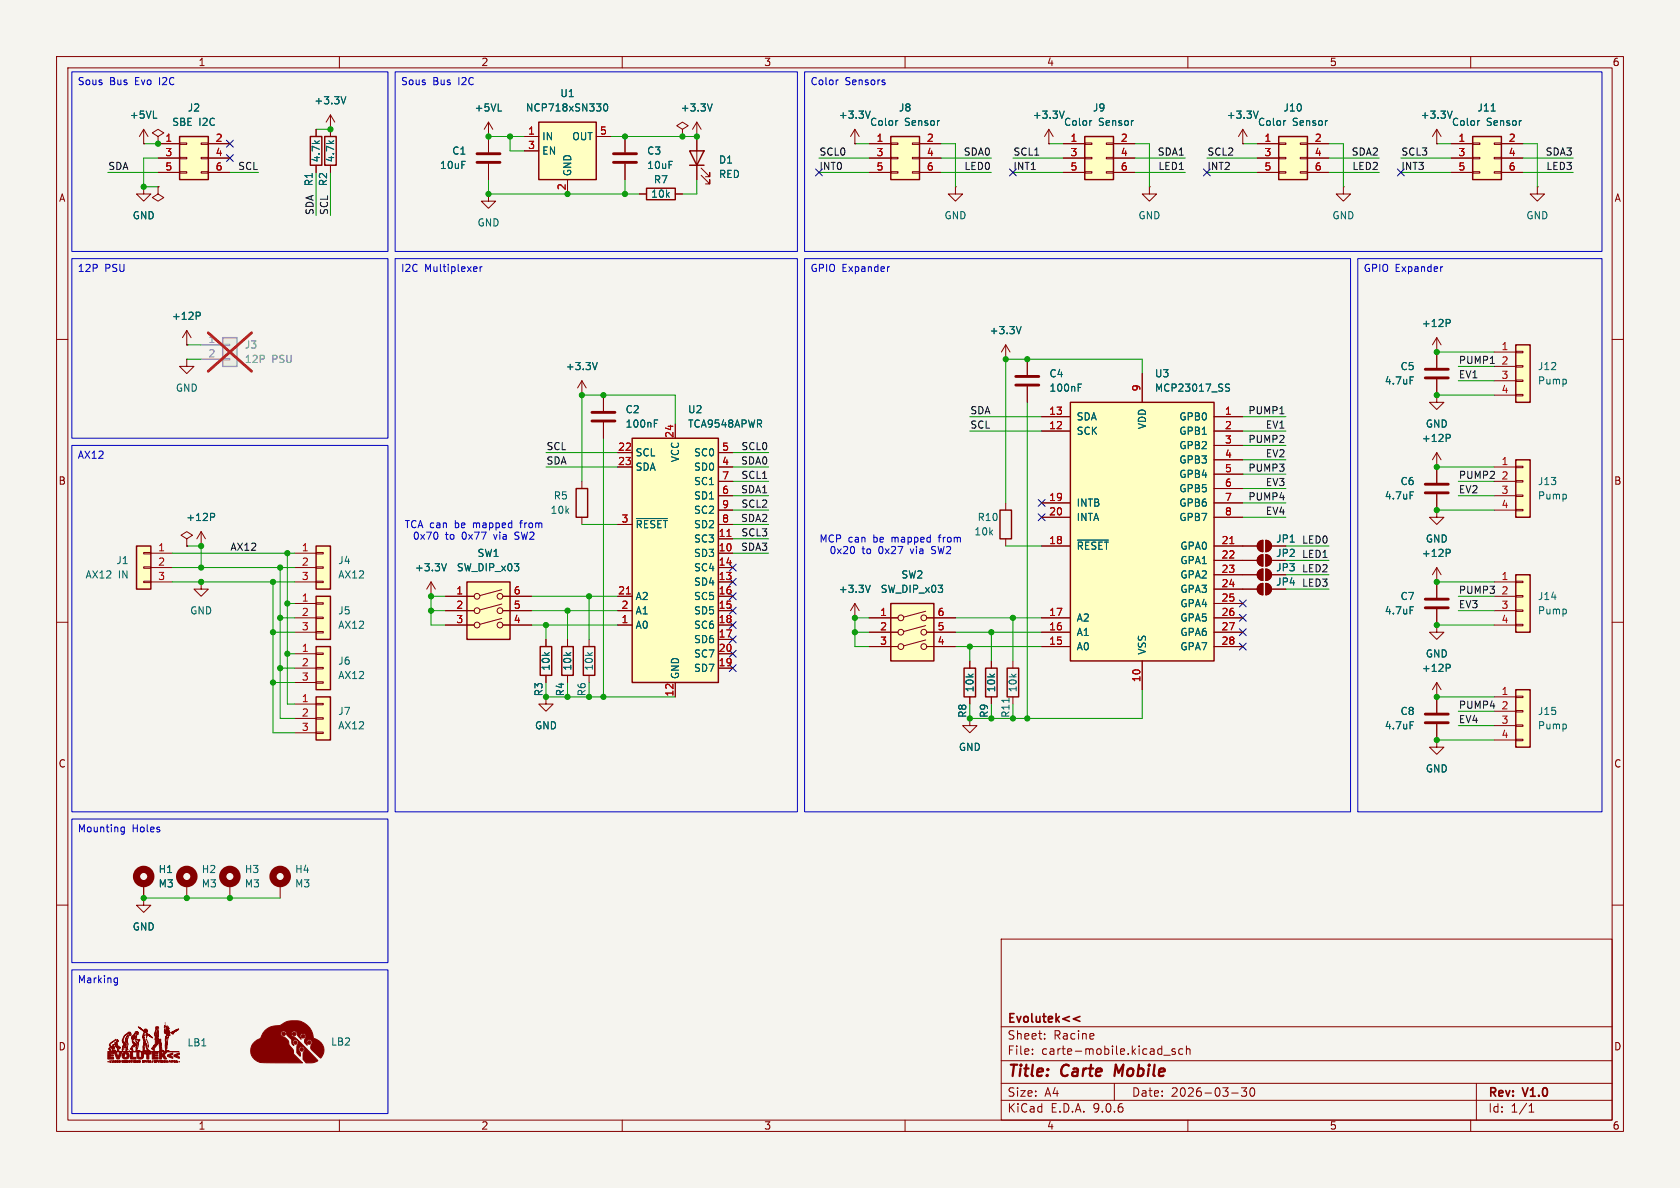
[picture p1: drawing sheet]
<svg xmlns="http://www.w3.org/2000/svg" width="297mm" height="210mm" viewBox="0 0 297 210" stroke-linecap="round" stroke-linejoin="round" font-family="sans-serif">
<defs><g id="words">
<g font-size="2.8" fill="#840000">
<text x="178" y="190.9">Title:</text>
<text x="187.7" y="190.9">Carte</text>
<text x="197.9" y="190.9">Mobile</text>
</g>
<g font-size="2.1" fill="#840000">
<text x="178" y="184">Sheet:</text>
<text x="178" y="181.2">Evolutek&lt;&lt;</text>
<text x="186.2" y="184">Racine</text>
<text x="178" y="186.7">File:</text>
<text x="184.1" y="186.7">carte-mobile.kicad_sch</text>
<text x="178" y="196.9">KiCad</text>
<text x="178" y="194.1">Size:</text>
<text x="184.7" y="194.1">A4</text>
<text x="185.7" y="196.9">E.D.A.</text>
<text x="193.3" y="196.9">9.0.6</text>
<text x="200" y="194.1">Date:</text>
<text x="207" y="194.1">2026-03-30</text>
<text x="263" y="194.3">Rev:</text>
<text x="263" y="196.9">Id:</text>
<text x="267.1" y="196.9">1/1</text>
<text x="269.4" y="194.3">V1.0</text>
</g>
<g font-size="1.8" fill="#840000">
<text x="35" y="11.9">1</text>
<text x="85" y="11.9">2</text>
<text x="135" y="11.9">3</text>
<text x="185" y="11.9">4</text>
<text x="235" y="11.9">5</text>
<text x="285" y="11.9">6</text>
<text x="10.3" y="35.9">A</text>
<text x="285.3" y="35.9">A</text>
<text x="10.3" y="85.9">B</text>
<text x="285.3" y="85.9">B</text>
<text x="96.1" y="123.2" transform="rotate(-90 96.1 123.2)">R3</text>
<text x="171" y="127" transform="rotate(-90 171 127)">R8</text>
<text x="10.3" y="135.9">C</text>
<text x="285.3" y="135.9">C</text>
<text x="10.3" y="185.9">D</text>
<text x="285.3" y="185.9">D</text>
<text x="35" y="199.9">1</text>
<text x="85" y="199.9">2</text>
<text x="135" y="199.9">3</text>
<text x="185" y="199.9">4</text>
<text x="235" y="199.9">5</text>
<text x="285" y="199.9">6</text>
</g>
<g font-size="1.8" fill="#0000c2">
<text x="13.7" y="15.4">Sous</text>
<text x="19.4" y="15.4">Bus</text>
<text x="24" y="15.4">Evo</text>
<text x="28.4" y="15.4">I2C</text>
<text x="70.8" y="15.4">Sous</text>
<text x="76.5" y="15.4">Bus</text>
<text x="81.1" y="15.4">I2C</text>
<text x="143.2" y="15.4">Color</text>
<text x="149.4" y="15.4">Sensors</text>
<text x="13.7" y="48.4">12P</text>
<text x="18.5" y="48.4">PSU</text>
<text x="70.8" y="48.4">I2C</text>
<text x="75.1" y="48.4">Multiplexer</text>
<text x="143.2" y="48.4">GPIO Expander</text>
<text x="241" y="48.4">GPIO Expander</text>
<text x="13.7" y="81.4">AX12</text>
<text x="71.4" y="93.6">TCA can</text>
<text x="72.9" y="95.6">0x70</text>
<text x="78.7" y="95.6">to</text>
<text x="80.5" y="93.6">be</text>
<text x="81.8" y="95.6">0x77</text>
<text x="83.9" y="93.6">mapped</text>
<text x="87.6" y="95.6">via</text>
<text x="91.5" y="95.6">SW2</text>
<text x="92.5" y="93.6">from</text>
<text x="144.8" y="96.1">MCP can</text>
<text x="146.6" y="98.2">0x20</text>
<text x="152.4" y="98.2">to</text>
<text x="154.5" y="96.1">be</text>
<text x="155.4" y="98.2">0x27</text>
<text x="157.9" y="96.1">mapped</text>
<text x="161.3" y="98.2">via</text>
<text x="165.1" y="98.2">SW2</text>
<text x="166.4" y="96.1">from</text>
<text x="13.7" y="147.5">Mounting</text>
<text x="23.4" y="147.5">Holes</text>
<text x="13.7" y="174.1">Marking</text>
</g>
<g font-size="1.8" fill="#006464">
<text x="99" y="17.4">U1</text>
<text x="22.8" y="21.2">+5VL</text>
<text x="30.3" y="22.5">SBE</text>
<text x="33.1" y="19.9">J2</text>
<text x="35.1" y="22.5">I2C</text>
<text x="55.5" y="18.6">+3.3V</text>
<text x="83.8" y="19.9">+5VL</text>
<text x="92.9" y="19.9">NCP718xSN330</text>
<text x="120.2" y="19.9">+3.3V</text>
<text x="148.2" y="21.2">+3.3V</text>
<text x="153.7" y="22.5">Color</text>
<text x="158.8" y="19.9">J8</text>
<text x="159.9" y="22.5">Sensor</text>
<text x="182.5" y="21.2">+3.3V</text>
<text x="188" y="22.5">Color</text>
<text x="193.1" y="19.9">J9</text>
<text x="194.2" y="22.5">Sensor</text>
<text x="216.8" y="21.2">+3.3V</text>
<text x="222.3" y="22.5">Color</text>
<text x="226.8" y="19.9">J10</text>
<text x="228.5" y="22.5">Sensor</text>
<text x="251.1" y="21.2">+3.3V</text>
<text x="256.6" y="22.5">Color</text>
<text x="261.1" y="19.9">J11</text>
<text x="262.8" y="22.5">Sensor</text>
<text x="56.7" y="28.8" transform="rotate(-90 56.7 28.8)">4.7k</text>
<text x="59.3" y="28.8" transform="rotate(-90 59.3 28.8)">4.7k</text>
<text x="79.9" y="27.5">C1</text>
<text x="95.8" y="25">IN</text>
<text x="95.8" y="27.5">EN</text>
<text x="101.1" y="25">OUT</text>
<text x="114.3" y="27.5">C3</text>
<text x="127" y="29.1">D1</text>
<text x="55.5" y="33" transform="rotate(-90 55.5 33)">R1</text>
<text x="58" y="33" transform="rotate(-90 58 33)">R2</text>
<text x="77.7" y="30.1">10uF</text>
<text x="101.2" y="31.2" transform="rotate(-90 101.2 31.2)">GND</text>
<text x="114.3" y="30.1">10uF</text>
<text x="115" y="35.2">10k</text>
<text x="115.5" y="32.6">R7</text>
<text x="127" y="31.7">RED</text>
<text x="23.4" y="39">GND</text>
<text x="84.3" y="40.2">GND</text>
<text x="166.9" y="39">GND</text>
<text x="201.2" y="39">GND</text>
<text x="235.5" y="39">GND</text>
<text x="269.7" y="39">GND</text>
<text x="30.3" y="56.7">+12P</text>
<text x="174.9" y="59.3">+3.3V</text>
<text x="251.3" y="58">+12P</text>
<text x="99.9" y="65.6">+3.3V</text>
<text x="247.5" y="65.6">C5</text>
<text x="271.8" y="65.6">J12</text>
<text x="31" y="69.4">GND</text>
<text x="185.4" y="66.9">C4</text>
<text x="185.4" y="69.4">100nF</text>
<text x="204.1" y="69.4">MCP23017_SS</text>
<text x="204.1" y="66.9">U3</text>
<text x="244.7" y="68.2">4.7uF</text>
<text x="271.8" y="68.2">Pump</text>
<text x="110.5" y="73.3">C2</text>
<text x="110.5" y="75.8">100nF</text>
<text x="121.5" y="73.3">U2</text>
<text x="121.5" y="75.8">TCA9548APWR</text>
<text x="190.2" y="74.5">SDA</text>
<text x="190.2" y="77.1">SCK</text>
<text x="202.8" y="76" transform="rotate(-90 202.8 76)">VDD</text>
<text x="208.4" y="74.5">GPB0</text>
<text x="208.4" y="77.1">GPB1</text>
<text x="252" y="75.8">GND</text>
<text x="112.3" y="80.9">SCL</text>
<text x="112.3" y="83.4">SDA</text>
<text x="120.2" y="81.8" transform="rotate(-90 120.2 81.8)">VCC</text>
<text x="122.6" y="80.9">SC0</text>
<text x="122.6" y="83.4">SD0</text>
<text x="208.4" y="79.6">GPB2</text>
<text x="208.4" y="82.1">GPB3</text>
<text x="251.3" y="78.3">+12P</text>
<text x="97.8" y="88.5">R5</text>
<text x="122.6" y="86">SC1</text>
<text x="122.6" y="88.5">SD1</text>
<text x="190.2" y="89.8">INTB</text>
<text x="208.4" y="84.7">GPB4</text>
<text x="208.4" y="87.2">GPB5</text>
<text x="208.4" y="89.8">GPB6</text>
<text x="244.7" y="88.5">4.7uF</text>
<text x="247.5" y="86">C6</text>
<text x="271.8" y="88.5">Pump</text>
<text x="271.8" y="86">J13</text>
<text x="32.8" y="92.3">+12P</text>
<text x="97.2" y="91">10k</text>
<text x="112.3" y="93.6">~{RESET}</text>
<text x="122.6" y="91">SC2</text>
<text x="122.6" y="93.6">SD2</text>
<text x="172.2" y="94.8">10k</text>
<text x="172.7" y="92.3">R10</text>
<text x="190.2" y="92.3">INTA</text>
<text x="208.4" y="92.3">GPB7</text>
<text x="20.5" y="99.9">J1</text>
<text x="59.7" y="99.9">J4</text>
<text x="73.3" y="101.2">+3.3V</text>
<text x="80.7" y="101.2">SW_DIP_x03</text>
<text x="84.3" y="98.7">SW1</text>
<text x="122.6" y="96.1">SC3</text>
<text x="122.6" y="98.7">SD3</text>
<text x="122.6" y="101.2">SC4</text>
<text x="190.2" y="97.4">~{RESET}</text>
<text x="208.6" y="97.4">GPA0</text>
<text x="208.6" y="99.9">GPA1</text>
<text x="225.5" y="96.1">JP1</text>
<text x="225.5" y="98.7">JP2</text>
<text x="225.5" y="101.2">JP3</text>
<text x="251.3" y="98.7">+12P</text>
<text x="252" y="96.1">GND</text>
<text x="15" y="102.5">AX12</text>
<text x="20.9" y="102.5">IN</text>
<text x="59.7" y="102.5">AX12</text>
<text x="112.3" y="106.3">A2</text>
<text x="122.6" y="103.7">SD4</text>
<text x="122.6" y="106.3">SC5</text>
<text x="148.2" y="105">+3.3V</text>
<text x="155.6" y="105">SW_DIP_x03</text>
<text x="159.3" y="102.5">SW2</text>
<text x="208.6" y="102.5">GPA2</text>
<text x="208.6" y="105">GPA3</text>
<text x="208.6" y="107.5">GPA4</text>
<text x="225.5" y="103.7">JP4</text>
<text x="247.5" y="106.3">C7</text>
<text x="271.8" y="106.3">J14</text>
<text x="33.5" y="108.8">GND</text>
<text x="59.7" y="108.8">J5</text>
<text x="59.7" y="111.4">AX12</text>
<text x="112.3" y="108.8">A1</text>
<text x="112.3" y="111.4">A0</text>
<text x="122.6" y="108.8">SD5</text>
<text x="122.6" y="111.4">SC6</text>
<text x="122.6" y="113.9">SD6</text>
<text x="190.2" y="110.1">A2</text>
<text x="190.2" y="112.6">A1</text>
<text x="208.6" y="110.1">GPA5</text>
<text x="208.6" y="112.6">GPA6</text>
<text x="244.7" y="108.8">4.7uF</text>
<text x="271.8" y="108.8">Pump</text>
<text x="59.7" y="117.7">J6</text>
<text x="97.4" y="118.7" transform="rotate(-90 97.4 118.7)">10k</text>
<text x="101.2" y="118.7" transform="rotate(-90 101.2 118.7)">10k</text>
<text x="105" y="118.7" transform="rotate(-90 105 118.7)">10k</text>
<text x="122.6" y="116.4">SC7</text>
<text x="122.6" y="119">SD7</text>
<text x="190.2" y="115.2">A0</text>
<text x="202.8" y="115.8" transform="rotate(-90 202.8 115.8)">VSS</text>
<text x="208.6" y="115.2">GPA7</text>
<text x="251.3" y="119">+12P</text>
<text x="252" y="116.4">GND</text>
<text x="59.7" y="120.2">AX12</text>
<text x="99.9" y="123.2" transform="rotate(-90 99.9 123.2)">R4</text>
<text x="120.2" y="120.1" transform="rotate(-90 120.2 120.1)">GND</text>
<text x="172.3" y="122.5" transform="rotate(-90 172.3 122.5)">10k</text>
<text x="176.1" y="122.5" transform="rotate(-90 176.1 122.5)">10k</text>
<text x="179.9" y="122.5" transform="rotate(-90 179.9 122.5)">10k</text>
<text x="59.7" y="126.6">J7</text>
<text x="59.7" y="129.1">AX12</text>
<text x="94.5" y="129.1">GND</text>
<text x="174.9" y="127" transform="rotate(-90 174.9 127)">R9</text>
<text x="244.7" y="129.1">4.7uF</text>
<text x="247.5" y="126.6">C8</text>
<text x="271.8" y="129.1">Pump</text>
<text x="271.8" y="126.6">J15</text>
<text x="169.4" y="132.9">GND</text>
<text x="252" y="136.8">GND</text>
<text x="27.9" y="154.5">H1</text>
<text x="35.6" y="154.5">H2</text>
<text x="43.2" y="154.5">H3</text>
<text x="52.1" y="154.5">H4</text>
<text x="27.9" y="157.1">M3</text>
<text x="35.6" y="157.1">M3</text>
<text x="43.2" y="157.1">M3</text>
<text x="52.1" y="157.1">M3</text>
<text x="23.4" y="164.7">GND</text>
<text x="33" y="185.2">LB1</text>
<text x="58.4" y="185">LB2</text>
</g>
<g font-size="1.8" fill="#a90000">
<text x="93.3" y="23.9">1</text>
<text x="106" y="23.9">5</text>
<text x="29.1" y="25.1">1</text>
<text x="29.1" y="27.7">3</text>
<text x="38" y="25.1">2</text>
<text x="38" y="27.7">4</text>
<text x="93.3" y="26.4">3</text>
<text x="154.9" y="25.1">1</text>
<text x="154.9" y="27.7">3</text>
<text x="163.8" y="25.1">2</text>
<text x="163.8" y="27.7">4</text>
<text x="189.2" y="25.1">1</text>
<text x="189.2" y="27.7">3</text>
<text x="198" y="25.1">2</text>
<text x="198" y="27.7">4</text>
<text x="223.4" y="25.1">1</text>
<text x="223.4" y="27.7">3</text>
<text x="232.3" y="25.1">2</text>
<text x="232.3" y="27.7">4</text>
<text x="257.7" y="25.1">1</text>
<text x="257.7" y="27.7">3</text>
<text x="266.6" y="25.1">2</text>
<text x="266.6" y="27.7">4</text>
<text x="29.1" y="30.2">5</text>
<text x="38" y="30.2">6</text>
<text x="100.1" y="33.7" transform="rotate(-90 100.1 33.7)">2</text>
<text x="154.9" y="30.2">5</text>
<text x="163.8" y="30.2">6</text>
<text x="189.2" y="30.2">5</text>
<text x="198" y="30.2">6</text>
<text x="223.4" y="30.2">5</text>
<text x="232.3" y="30.2">6</text>
<text x="257.7" y="30.2">5</text>
<text x="266.6" y="30.2">6</text>
<text x="265.4" y="62">1</text>
<text x="265.4" y="64.5">2</text>
<text x="201.7" y="69.3" transform="rotate(-90 201.7 69.3)">9</text>
<text x="265.4" y="67.1">3</text>
<text x="265.4" y="69.6">4</text>
<text x="119.1" y="77.5" transform="rotate(-90 119.1 77.5)">24</text>
<text x="185.4" y="73.4">13</text>
<text x="185.4" y="75.9">12</text>
<text x="216.5" y="73.4">1</text>
<text x="216.5" y="75.9">2</text>
<text x="109.2" y="79.8">22</text>
<text x="109.2" y="82.3">23</text>
<text x="127.6" y="79.8">5</text>
<text x="127.6" y="82.3">4</text>
<text x="216.5" y="78.5">3</text>
<text x="216.5" y="81">4</text>
<text x="216.5" y="83.6">5</text>
<text x="265.4" y="82.3">1</text>
<text x="127.6" y="84.8">7</text>
<text x="127.6" y="87.4">6</text>
<text x="127.6" y="89.9">9</text>
<text x="185.4" y="88.6">19</text>
<text x="216.5" y="86.1">6</text>
<text x="216.5" y="88.6">7</text>
<text x="265.4" y="84.8">2</text>
<text x="265.4" y="87.4">3</text>
<text x="265.4" y="89.9">4</text>
<text x="109.8" y="92.5">3</text>
<text x="127" y="95">11</text>
<text x="127.6" y="92.5">8</text>
<text x="185.4" y="91.2">20</text>
<text x="216.5" y="91.2">8</text>
<text x="27.9" y="97.5">1</text>
<text x="27.9" y="100.1">2</text>
<text x="53.3" y="97.5">1</text>
<text x="53.3" y="100.1">2</text>
<text x="127" y="97.5">10</text>
<text x="127" y="100.1">14</text>
<text x="185.4" y="96.3">18</text>
<text x="215.9" y="96.3">21</text>
<text x="215.9" y="98.8">22</text>
<text x="215.9" y="101.3">23</text>
<text x="27.9" y="102.6">3</text>
<text x="53.3" y="106.4">1</text>
<text x="53.3" y="102.6">3</text>
<text x="80.6" y="105.2">1</text>
<text x="80.6" y="107.7">2</text>
<text x="90.7" y="105.2">6</text>
<text x="90.7" y="107.7">5</text>
<text x="109.2" y="105.2">21</text>
<text x="109.8" y="107.7">2</text>
<text x="127" y="102.6">13</text>
<text x="127" y="105.2">16</text>
<text x="127" y="107.7">15</text>
<text x="215.9" y="103.9">24</text>
<text x="215.9" y="106.4">25</text>
<text x="265.4" y="102.6">1</text>
<text x="265.4" y="105.2">2</text>
<text x="265.4" y="107.7">3</text>
<text x="53.3" y="109">2</text>
<text x="53.3" y="111.5">3</text>
<text x="80.6" y="110.2">3</text>
<text x="90.7" y="110.2">4</text>
<text x="109.8" y="110.2">1</text>
<text x="127" y="110.2">18</text>
<text x="127" y="112.8">17</text>
<text x="155.5" y="109">1</text>
<text x="155.5" y="111.5">2</text>
<text x="165.7" y="109">6</text>
<text x="165.7" y="111.5">5</text>
<text x="185.4" y="109">17</text>
<text x="185.4" y="111.5">16</text>
<text x="215.9" y="109">26</text>
<text x="215.9" y="111.5">27</text>
<text x="265.4" y="110.2">4</text>
<text x="53.3" y="115.3">1</text>
<text x="53.3" y="117.9">2</text>
<text x="127" y="115.3">20</text>
<text x="127" y="117.9">19</text>
<text x="155.5" y="114">3</text>
<text x="165.7" y="114">4</text>
<text x="185.4" y="114">15</text>
<text x="215.9" y="114">28</text>
<text x="53.3" y="124.2">1</text>
<text x="53.3" y="120.4">3</text>
<text x="119.1" y="123.2" transform="rotate(-90 119.1 123.2)">12</text>
<text x="201.7" y="120.7" transform="rotate(-90 201.7 120.7)">10</text>
<text x="265.4" y="122.9">1</text>
<text x="265.4" y="125.5">2</text>
<text x="53.3" y="126.7">2</text>
<text x="53.3" y="129.3">3</text>
<text x="265.4" y="128">3</text>
<text x="265.4" y="130.6">4</text>
</g>
<g font-size="1.8" fill="#0f0f0f">
<text x="144.8" y="27.6">SCL0</text>
<text x="170.3" y="27.6">SDA0</text>
<text x="179.1" y="27.6">SCL1</text>
<text x="204.6" y="27.6">SDA1</text>
<text x="213.4" y="27.6">SCL2</text>
<text x="238.9" y="27.6">SDA2</text>
<text x="247.6" y="27.6">SCL3</text>
<text x="273.1" y="27.6">SDA3</text>
<text x="19" y="30.1">SDA</text>
<text x="42" y="30.1">SCL</text>
<text x="144.8" y="30.1">INT0</text>
<text x="170.4" y="30.1">LED0</text>
<text x="179.1" y="30.1">INT1</text>
<text x="204.7" y="30.1">LED1</text>
<text x="213.4" y="30.1">INT2</text>
<text x="239" y="30.1">LED2</text>
<text x="247.6" y="30.1">INT3</text>
<text x="273.3" y="30.1">LED3</text>
<text x="55.5" y="38.1" transform="rotate(-90 55.5 38.1)">SDA</text>
<text x="58.1" y="38.1" transform="rotate(-90 58.1 38.1)">SCL</text>
<text x="257.8" y="64.4">PUMP1</text>
<text x="257.8" y="67">EV1</text>
<text x="171.4" y="73.3">SDA</text>
<text x="171.4" y="75.9">SCL</text>
<text x="220.6" y="73.3">PUMP1</text>
<text x="223.7" y="75.9">EV1</text>
<text x="96.5" y="79.7">SCL</text>
<text x="96.5" y="82.2">SDA</text>
<text x="130.9" y="82.2">SDA0</text>
<text x="131" y="79.7">SCL0</text>
<text x="220.6" y="83.5">PUMP3</text>
<text x="220.6" y="78.4">PUMP2</text>
<text x="223.7" y="80.9">EV2</text>
<text x="130.9" y="87.3">SDA1</text>
<text x="131" y="89.8">SCL2</text>
<text x="131" y="84.7">SCL1</text>
<text x="220.6" y="88.6">PUMP4</text>
<text x="223.7" y="86">EV3</text>
<text x="257.8" y="87.3">EV2</text>
<text x="257.8" y="84.7">PUMP2</text>
<text x="130.9" y="92.4">SDA2</text>
<text x="131" y="94.9">SCL3</text>
<text x="223.7" y="91.1">EV4</text>
<text x="40.6" y="97.4">AX12</text>
<text x="130.9" y="97.4">SDA3</text>
<text x="230.1" y="101.3">LED2</text>
<text x="230.1" y="98.7">LED1</text>
<text x="230.1" y="96.2">LED0</text>
<text x="230.1" y="103.8">LED3</text>
<text x="257.8" y="105.1">PUMP3</text>
<text x="257.8" y="107.6">EV3</text>
<text x="257.8" y="125.4">PUMP4</text>
<text x="257.8" y="127.9">EV4</text>
</g>
<g font-size="1.8" fill="#a5a4a2">
<text x="36.8" y="60.7">1</text>
<text x="36.8" y="63.2">2</text>
</g>
<g font-size="1.8" fill="#939391">
<text x="43.2" y="61.8">J3</text>
<text x="43.2" y="64.4">12P</text>
<text x="48" y="64.4">PSU</text>
</g>
<g font-size="1.8" fill="#009600">
<text x="103.7" y="123.2" transform="rotate(-90 103.7 123.2)">R6</text>
<text x="178.7" y="127" transform="rotate(-90 178.7 127)">R11</text>
</g>
</g></defs>
<path d="M0 0h297v210h-297z" fill="#f5f4ef" stroke="#f5f4ef" stroke-width=".18"/>
<g fill="none" stroke="#840000" stroke-width=".18">
<path d="M10 10h277v190h-277zM12 12h273v186h-273zM60 10v2M110 10v2M160 10v2M210 10v2M260 10v2M25.4 33v1.3h1.3l-1.3 1.3-1.3-1.3h1.3M25.4 33h.1M25.4 25.4h.1M25.4 22.9l-.8 1.2M25.4 22.9l.8 1.2"/>
<path d="M25.4 22.9v2.5M27.9 33v1.3l1.1 .6-1.1 .7-1-.7 1-.6M27.9 33h.1M27.9 24.1l1.1-.6-1.1-.6-1 .6 1 .6v1.3M27.9 25.4h.1M120.6 22.9l1.1-.7-1.1-.6-1 .6 1 .7v1.2M120.6 24.1h.1M219.7 25.4h.1M219.7 22.9l-.8 1.2M219.7 22.9l.8 1.2M219.7 22.9v2.5M10 60h2"/>
<path d="M285 60h2M10 110h2M254 110.5v1.3h1.3l-1.3 1.2-1.3-1.2h1.3M254 110.5h.1M285 110h2M10 160h2M177 166h108v32h-108zM285 160h2M60 198v2M110 198v2M160 198v2M177 194.5h108"/>
<path d="M177 191.5h108M177 187.5h108M177 181.5h108M182.5 186.3v.1M182.5 185.5v.1M184.7 183.6v.1M184.7 182.8v.1M193.3 182.8l.1 .3-.7 .1M197 191.5v3M205.7 186.5h1.2M207.7 185.5l-.3-.1-.2 .2v.2l.5 .2v.3h-.5M209.1 185.5l-.4-.1-.3 .3v.4l.1 .2h.6"/>
<path d="M209.7 185.5l.3-.1 .3 .1 .1 .9M209.7 184.9v1.5M210 198v2M217.7 193.2h1.2M219.5 192.3h.9l-.5 .6 .4 .1v.7l-.2 .1h-.4l-.2-.1M221.1 192.4l.2-.1a.81 .81 0 0 1 .6 .6 .81 .81 0 0 1-.3 .8l-.1 .1a.81 .81 0 0 1-.4-1.4zM260 198v2M261 191.5v6.5M270.3 196.6h.9M270.3 195.5l.4-.4v1.5"/>
</g>
<path d="M197.3 188.2l-.3 2" fill="none" stroke="#840000" stroke-width=".4"/>
<path d="M190.9 179.7l-1.1 .4 1.1 .4" fill="none" stroke="#840000" stroke-width=".3"/>
<path d="M222.4 19.6l-.4 1.3M27.1 20.9h.6" fill="none" stroke="#006464" stroke-width=".18"/>
<path d="M31.7 24.1h5.1v7.7h-5.1z" fill="#ffffc2"/>
<path d="M31.7 24.1h5.1v7.7h-5.1zM57.4 24.1h2v5.1h-2z" fill="none" stroke="#840000" stroke-width=".25"/>
<g fill="none" stroke="#840000" stroke-width=".18">
<path d="M27.9 25.4h3.8M27.9 27.9h3.8M27.9 30.5h3.8M31.7 25.3h1.3v.2h-1.3zM31.7 27.8h1.3v.3h-1.3zM31.7 30.4h1.3v.2h-1.3zM35.6 25.3h1.2v.2h-1.2zM35.6 27.8h1.2v.3h-1.2zM35.6 30.4h1.2v.2h-1.2zM36.8 25.4h3.8M36.8 27.9h3.8M36.8 30.5h3.8"/>
<path d="M58.4 22.9v1.2M58.4 29.2v1.3"/>
</g>
<path d="M268 121.9h2.5v10.2h-2.5z" fill="#ffffc2"/>
<path d="M54.9 24.1h2v5.1h-2zM268 121.9h2.5v10.2h-2.5z" fill="none" stroke="#840000" stroke-width=".25"/>
<g fill="none" stroke="#840000" stroke-width=".18">
<path d="M55.9 22.9v1.2M55.9 29.2v1.3M254 59.7l-.8 1.3M254 59.7l.8 1.3M254 59.7v2.5M181.6 63.5v2.8M181.6 68.3v2.8M254 62.2h.1M219.7 96.5h2.5M222.5 95.8l.8-.3v2a1.02 1.02 0 0 1-1-.6 1.02 1.02 0 0 1 .2-1.1zM223.8 95.5a1.02 1.02 0 0 1 1 1 1.02 1.02 0 0 1-1 1zM224.8 96.5h2.5"/>
<path d="M264.2 123.2h3.8M264.2 125.7h3.8M264.2 128.3h3.8M264.2 130.8h3.8M268 123.1h1.2v.2h-1.2zM268 125.6h1.2v.3h-1.2zM268 128.1h1.2v.3h-1.2zM268 130.7h1.2v.2h-1.2z"/>
</g>
<path d="M255.7 56.5h.4l.3 .2-.1 .4h-.6M190.6 68.5h.4M190.6 67.9h.6" fill="none" stroke="#006464" stroke-width=".18"/>
<g fill="#840000" stroke="#840000" stroke-width=".18">
<path d="M222.5 95.8l.8-.3v2a1.02 1.02 0 0 1-1-.6 1.02 1.02 0 0 1 .2-1.1z"/>
<path d="M223.8 95.5a1.02 1.02 0 0 1 1 1 1.02 1.02 0 0 1-1 1z"/>
</g>
<path d="M179.6 66.5h4M179.6 68.1h4" fill="none" stroke="#840000" stroke-width=".51"/>
<path d="M268 81.3h2.5v10.1h-2.5z" fill="#ffffc2"/>
<path d="M268 81.3h2.5v10.1h-2.5z" fill="none" stroke="#840000" stroke-width=".25"/>
<path d="M264.2 82.6h3.8M264.2 85.1h3.8M264.2 87.6h3.8M264.2 90.2h3.8M268 82.4h1.2v.3h-1.2zM268 85h1.2v.2h-1.2zM268 87.5h1.2v.3h-1.2zM268 90h1.2v.3h-1.2z" fill="none" stroke="#840000" stroke-width=".18"/>
<path d="M189.2 71.1h25.4v45.7h-25.4z" fill="#ffffc2"/>
<path d="M189.2 71.1h25.4v45.7h-25.4z" fill="none" stroke="#840000" stroke-width=".25"/>
<g fill="none" stroke="#840000" stroke-width=".18">
<path d="M184.1 73.7h5.1M184.1 76.2h5.1M201.9 66v5.1M214.6 73.7h5.1M214.6 76.2h5.1M214.6 78.7h5.1M184.1 88.9h5.1M184.1 91.4h5.1M184.1 96.5h5.1M214.6 88.9h5.1M214.6 91.4h5.1M214.6 96.5h5.1"/>
<path d="M214.6 81.3h5.1M214.6 83.8h5.1M214.6 86.4h5.1M214.6 99.1h7.6M222.5 98.3l.8-.3v2.1a1.02 1.02 0 0 1-1-.7 1.02 1.02 0 0 1 .2-1.1zM223.8 98a1.02 1.02 0 0 1 1 1.1 1.02 1.02 0 0 1-1 1zM224.8 99.1h2.5M184.1 109.2h5.1M184.1 111.8h5.1M184.1 114.3h5.1M201.9 116.8v5.1M214.6 109.2h5.1"/>
<path d="M214.6 111.8h5.1M214.6 114.3h5.1M214.6 101.6h5.1M214.6 104.1h5.1M214.6 106.7h5.1"/>
</g>
<path d="M216.8 68.4l.4 .2 .2 .3-.3 .3-.5-.1M216.8 68h.6M190.5 95.5h5.5" fill="none" stroke="#006464" stroke-width=".18"/>
<path d="M217.4 96.1h.7" fill="none" stroke="#a90000" stroke-width=".18"/>
<g fill="#840000" stroke="#840000" stroke-width=".18">
<path d="M222.5 98.3l.8-.3v2.1a1.02 1.02 0 0 1-1-.7 1.02 1.02 0 0 1 .2-1.1z"/>
<path d="M223.8 98a1.02 1.02 0 0 1 1 1.1 1.02 1.02 0 0 1-1 1z"/>
</g>
<path d="M268 61h2.5v10.1h-2.5z" fill="#ffffc2"/>
<path d="M268 61h2.5v10.1h-2.5z" fill="none" stroke="#840000" stroke-width=".25"/>
<path d="M264.2 62.2h3.8M264.2 64.8h3.8M264.2 67.3h3.8M264.2 69.9h3.8M268 62.1h1.2v.3h-1.2zM268 64.6h1.2v.3h-1.2zM268 67.2h1.2v.2h-1.2zM268 69.7h1.2v.3h-1.2zM254 102.9h.1M254 100.3l-.8 1.3M254 100.3l.8 1.3M254 100.3v2.6" fill="none" stroke="#840000" stroke-width=".18"/>
<path d="M255.7 97.1h.4l.3 .2-.1 .4-.6 .1" fill="none" stroke="#006464" stroke-width=".18"/>
<path d="M268 101.6h2.5v10.2h-2.5z" fill="#ffffc2"/>
<path d="M268 101.6h2.5v10.2h-2.5z" fill="none" stroke="#840000" stroke-width=".25"/>
<g fill="none" stroke="#840000" stroke-width=".18">
<path d="M58.4 22.9h.1M58.4 20.3l-.7 1.3M58.4 20.3l.8 1.3M58.4 20.3v2.6M33 58.4l-.7 1.3M33 58.4l.8 1.3M33 58.4v2.6M33 63.5v1.3h1.3l-1.3 1.2-1.3-1.2h1.3M33 63.5h.1M33 61h.1M254 102.9v2.8M254 107.7v2.8"/>
<path d="M264.2 102.9h3.8M264.2 105.4h3.8M264.2 108h3.8M264.2 110.5h3.8M268 102.7h1.2v.3h-1.2zM268 105.3h1.2v.2h-1.2zM268 107.8h1.2v.3h-1.2zM268 110.4h1.2v.2h-1.2zM254 130.8v1.3h1.3l-1.3 1.3-1.3-1.3h1.3M254 130.8h.1M254 123.2v2.8M254 128v2.8"/>
</g>
<path d="M61.1 17.1l-.4 1.3M34.7 55.2h.5l.2 .2-.1 .4-.6 .1M249.3 107.3h.6M249.3 127.6h.6" fill="none" stroke="#006464" stroke-width=".18"/>
<path d="M252 105.9h4M252 107.4h4M252 126.2h4M252 127.8h4" fill="none" stroke="#840000" stroke-width=".51"/>
<path d="M191.8 24.1h5v7.7h-5z" fill="#ffffc2"/>
<path d="M191.8 24.1h5v7.7h-5z" fill="none" stroke="#840000" stroke-width=".25"/>
<g fill="none" stroke="#840000" stroke-width=".18">
<path d="M188 25.4h3.8M188 27.9h3.8M188 30.5h3.8M191.8 25.3h1.2v.2h-1.2zM191.8 27.8h1.2v.3h-1.2zM191.8 30.4h1.2v.2h-1.2zM195.6 25.3h1.2v.2h-1.2zM195.6 27.8h1.2v.3h-1.2zM195.6 30.4h1.2v.2h-1.2zM196.8 25.4h3.9M196.8 27.9h3.9M196.8 30.5h3.9"/>
<path d="M203.2 33v1.3h1.3l-1.3 1.3-1.3-1.3h1.3M203.2 33h.1"/>
</g>
<path d="M193 21.3l-.2 .1" fill="none" stroke="#006464" stroke-width=".18"/>
<path d="M157.5 24.1h5.1v7.7h-5.1z" fill="#ffffc2"/>
<path d="M157.5 24.1h5.1v7.7h-5.1z" fill="none" stroke="#840000" stroke-width=".25"/>
<g fill="none" stroke="#840000" stroke-width=".18">
<path d="M151.1 25.4h.1M151.1 22.9l-.7 1.2M151.1 22.9l.8 1.2M151.1 22.9v2.5M153.7 25.4h3.8M153.7 27.9h3.8M153.7 30.5h3.8M157.5 25.3h1.2v.2h-1.2zM157.5 27.8h1.2v.3h-1.2zM157.5 30.4h1.2v.2h-1.2zM161.3 25.3h1.3v.2h-1.3zM161.3 27.8h1.3v.3h-1.3z"/>
<path d="M161.3 30.4h1.3v.2h-1.3zM162.6 25.4h3.8M162.6 27.9h3.8M162.6 30.5h3.8M185.4 25.4h.1M185.4 22.9l-.7 1.2M185.4 22.9l.8 1.2M185.4 22.9v2.5"/>
</g>
<path d="M153.9 19.6l-.5 1.3M188.1 19.6l-.4 1.3M158.7 21.3l-.2 .1" fill="none" stroke="#006464" stroke-width=".18"/>
<path d="M39.4 59.7h2.5v5.1h-2.5z" fill="#ebeae8"/>
<path d="M39.4 59.7h2.5v5.1h-2.5z" fill="none" stroke="#9c9b98" stroke-width=".25"/>
<path d="M35.6 61h3.8M35.6 63.5h3.8M39.4 60.8h1.2v.3h-1.2zM39.4 63.4h1.2v.2h-1.2z" fill="none" stroke="#9c9b98" stroke-width=".18"/>
<path d="M36.8 58.8l7.7 6.8M44.5 58.8l-7.7 6.8" fill="none" stroke="#e12e31" stroke-width=".46"/>
<g fill="#840000" stroke="#840000" stroke-width=".18">
<path d="M46.8 182.2a4.1 4.1 0 0 1 2.8-1 3.9 3.9 0 0 1 4.8 .1 4.6 4.6 0 0 1 1.1 2.3 2.04 2.04 0 0 1 1.7 1.3 2.04 2.04 0 0 1-.5 2.1l-.7-.5a2.08 2.08 0 0 1-1.1-1.4l.1-.3a.55 .55 0 0 0 0-.9 .55 .55 0 0 0-.8 .5l.1 .4a.86 .86 0 0 1-.2-1.4 .53 .53 0 0 0-.6-.7 .53 .53 0 0 0-.4 .8l.1 .2-.6-.7a.6 .6 0 0 0-.3-.7 .6 .6 0 0 0-.7 .1 .62 .62 0 0 0 .5 1l4.1 4.1-.8 .4h-1.3a1.24 1.24 0 0 1-.5-1.5v-.3a.57 .57 0 0 0 .2-.9 .57 .57 0 0 0-.9 0 .57 .57 0 0 0 .2 .8v.7a1.46 1.46 0 0 1-.6-1.7v-.2a.57 .57 0 0 0 .2-.8 .57 .57 0 0 0-.9-.1 .57 .57 0 0 0 .2 .9 .77 .77 0 0 1-.4-1l-.9-.9a.56 .56 0 0 0-.5-.7 .56 .56 0 0 0-.6 .7 .56 .56 0 0 0 .7 .4 1.51 1.51 0 0 1 .9 1.5l.1 .1a1.36 1.36 0 0 1 .6 1.4l1.6 1.6h-5.8a3.5 3.5 0 0 1-2.7-.6 2.19 2.19 0 0 1 1-3.7z"/>
<path d="M19.1 187.7h.1z"/>
<path d="M19.5 185.5v.1z"/>
<path d="M19.4 187.5l.3 .3h-.3z"/>
<path d="M19.7 187.5l.1 .1z"/>
<path d="M20 187.5h.1l.1 .3h-.4l.1-.2 .2 .1-.2-.1z"/>
<path d="M19.9 184.7l.1 .1 .3-.3-.2 .4z"/>
<path d="M19.1 186h1v.3h-.7v.2h.6v.2h-.6v.2h.7v.3h-1z"/>
<path d="M19.5 184.4l1-.7-.2 .3a1.04 1.04 0 0 0-.8 .8l.5 .3-.1 .6h.5h-.5v-.6l-.2 .2 .1-.2h-.2a.27 .27 0 0 0-.2 .2 .27 .27 0 0 0 0 .3l.2 .1a.27 .27 0 0 1-.3-.1 .27 .27 0 0 1 0-.3 .31 .31 0 0 0 .2-.3 .31 .31 0 0 0-.2-.3z"/>
<path d="M20.1 184.9l.1 .6z"/>
<path d="M20.3 187.5h.2l-.1 .1 .1 .1-.2 .1 .1-.1z"/>
<path d="M20.5 184.2l.1 .1z"/>
<path d="M20.6 184.4v.3z"/>
<path d="M20.7 184.3v.4z"/>
<path d="M20.6 187.5h.2l-.1 .1h.2a.15 .15 0 0 1-.1 .2 .15 .15 0 0 1-.2-.1h.2z"/>
<path d="M20.6 184l.2 .2-.2-.1 .2 .1z"/>
<path d="M20.3 184.3l.1 .1a.9 .9 0 0 0 .4 1l.1 .3h-.2l.1-.3a.85 .85 0 0 1-.4-1.1z"/>
<path d="M20.2 186h.4l.3 .9 .3-.9h.3l-.4 1.2a.45 .45 0 0 1-.5-.1 .45 .45 0 0 1-.1-.4z"/>
<path d="M20.8 183.8l.1 .3z"/>
<path d="M20.9 185.2v.1z"/>
<path d="M21 185.6v.1z"/>
<path d="M21 185.4v.1z"/>
<path d="M21 187.5a.18 .18 0 0 1 .3 .1 .18 .18 0 0 1-.1 .2 .18 .18 0 0 1-.2-.1h.2l-.1-.2-.1 .2z"/>
<path d="M20.6 184.8l.6 .5-.3-.3-.1 .2z"/>
<path d="M21.2 185.1l.1 .2z"/>
<path d="M21.6 187.5h.3v.3l-.2-.1-.1 .1v-.2h.2z"/>
<path d="M22 185.1l-.1 .1z"/>
<path d="M22.1 184.9v.1z"/>
<path d="M22 187.5h.1a.18 .18 0 0 1 .2 .1 .18 .18 0 0 1-.2 .2 .18 .18 0 0 1-.2-.1h.3l-.1-.2-.2 .2z"/>
<path d="M22.5 183v.1a1.36 1.36 0 0 0-.2 1.2l-.1-.6z"/>
<path d="M21.8 186.2a.65 .65 0 0 1 1 .1 .65 .65 0 0 1-.4 .9 .65 .65 0 0 1-.8-.7h.4v.2a.27 .27 0 0 0 .3 .3 .27 .27 0 0 0 .2-.4 .26 .26 0 0 0-.3-.3 .26 .26 0 0 0-.2 .2h-.4z"/>
<path d="M22 183a.74 .74 0 0 1 .8-.3l.1-.1-.4 .1 .1-.1a.28 .28 0 0 1 .3-.1 .28 .28 0 0 1 .2 .2v-.1l-.1 .1 .1 .3-.3-.1a.33 .33 0 0 0-.3-.2 .33 .33 0 0 0-.3 .2l-.1 .1a.87 .87 0 0 0 0 1.4 .52 .52 0 0 1 .2 .7l.1 .6h-.1l-.1-.9a.37 .37 0 0 0-.4 .1 .37 .37 0 0 0 0 .4v.3h-.2l.2-1h.5h-.5l-.1-.4 .5 .4-.5-.4-.1-.2z"/>
<path d="M22.3 187.5h.3v.3h-.3v-.1h.3h-.3v-.1h.2z"/>
<path d="M22.6 183.5l-.1 .7a.56 .56 0 0 1 .1-.7z"/>
<path d="M22.5 184.3v.1z"/>
<path d="M22.5 185.2v.2z"/>
<path d="M22.5 184.3l.1 .1z"/>
<path d="M22.5 184.9v.1z"/>
<path d="M22.5 185.4l.1 .2z"/>
<path d="M22.7 187.5a.18 .18 0 0 1 .3 0 .18 .18 0 0 1-.1 .3 .18 .18 0 0 1-.2-.2l.2 .1v-.1z"/>
<path d="M23.1 187.5h.3l-.1 .3z"/>
<path d="M23.4 185.3l.1 .3z"/>
<path d="M23.5 187.5v.3z"/>
<path d="M23.6 185.1l.2-.2z"/>
<path d="M23.7 187.5a.21 .21 0 0 1 .3 0 .21 .21 0 0 1 0 .3l-.3-.1v-.1l.2 .1-.1-.1h-.1z"/>
<path d="M23.1 186h.3v.9h.6v.3h-.9z"/>
<path d="M24.1 182.9v.2z"/>
<path d="M24 183.1v.2l.1-.1v.3z"/>
<path d="M24 184.1l.2 .1z"/>
<path d="M24.2 183.1v.1z"/>
<path d="M24.3 185.3v.2z"/>
<path d="M24.2 184.2l.1 .2z"/>
<path d="M24.1 187.5l.2 .2 .1-.2a.19 .19 0 0 1 0 .3 .19 .19 0 0 1-.3 0 .19 .19 0 0 1 0-.3z"/>
<path d="M24.5 184l-.1 .3z"/>
<path d="M24.3 184.4l.2 .3z"/>
<path d="M23.9 182.4a.32 .32 0 0 1 .6 .2l-.1-.1-.1 .1 .1 .2h-.1l-.1-.3-.1 .3h-.2a.71 .71 0 0 0 0 .7 .71 .71 0 0 0 .7 .4h.1l-.7-.1-.2-.2-.1-.5-.1 .6a.56 .56 0 0 0 .5 .8 .46 .46 0 0 1 0 .7 .4 .4 0 0 0 .1 .5 .4 .4 0 0 0 .5 0h-.7l.1-1-.1-.1v.1a.78 .78 0 0 0-.7 .8l.2 .2a.33 .33 0 0 1-.4-.2 .33 .33 0 0 1 .2-.4l.1-.2a.24 .24 0 0 0 .2-.2 .24 .24 0 0 0 0-.2h.3h-.3l-.1-.2 .3 .1h-.1a.57 .57 0 0 1-.4-.7v-.3l.2 .3 .1-.6-.3 .2z"/>
<path d="M24.6 183.7l.1 .1z"/>
<path d="M24.5 187.5h.3l-.2 .1h.2l-.2 .1 .2 .1h-.3z"/>
<path d="M24.2 186h.4v.9a.21 .21 0 0 0 .2 0 .21 .21 0 0 0 .2-.2v-.7h.4v.5a.6 .6 0 0 1-.6 .7 .6 .6 0 0 1-.6-.7z"/>
<path d="M25.2 187.5h.3l-.2 .1h.2l-.2 .1 .2 .1h-.3z"/>
<path d="M25.5 183.4v.2z"/>
<path d="M25.5 185.3v.1z"/>
<path d="M25.6 183l-.1 .1z"/>
<path d="M25.6 185.1v.1z"/>
<path d="M25.6 184.9v.1z"/>
<path d="M25.6 182.8v.1z"/>
<path d="M25.6 187.5l.2 .1-.2 .2v-.2h.1z"/>
<path d="M25.5 183.8l.1 .1z"/>
<path d="M25.9 183.3v.2z"/>
<path d="M25.8 183.7l.1 .1z"/>
<path d="M25.9 187.5l.1 .3z"/>
<path d="M26.2 184.7v.4z"/>
<path d="M26.1 187.5h.3l-.1 .3z"/>
<path d="M25.6 186h1.1v.3h-.4v.9h-.3l-.1-.9h-.3z"/>
<path d="M19 185.9h12.7z"/>
<path d="M24.5 181.5l.9 .7h.4h-.4a.3 .3 0 0 1 .3-.3 .3 .3 0 0 1 .3 .3l-.2-.2 .1 .3 .1 .1a.3 .3 0 0 0 .2 .5h.2l.6 .6-.7-.5-.4 .2v-.4l.1 .3 .2-.2-.3-.2-.2-.3a1.12 1.12 0 0 0 0 1.6l-.1 .2 .3 .5 .2 1 .4 .1h-.5l-.2-1.2a.7 .7 0 0 0-.4 1v.1h.3h-.4v-.7l.1-.5h.4h-.4v-.3h.3v.3v-.3h-.3v-.1a1.72 1.72 0 0 1 .1-1.7l-.1-.1 .6 .1-.6-.1z"/>
<path d="M26.5 187.5l.2 .3h-.3l.1-.2 .1 .1-.1-.1z"/>
<path d="M27 187.5v.3z"/>
<path d="M27.3 187.5h.3l-.2 .1h.2l-.2 .1 .2 .1h-.3z"/>
<path d="M27.6 187.5h.3l-.2 .3-.1-.2h.2h-.2z"/>
<path d="M27.5 181.6l.5-.1v.2h-.3v.3l-.2-.1z"/>
<path d="M27.8 182.4l-.1 .1z"/>
<path d="M27.7 182.6l.2 .7-.2 .1-.1-.6z"/>
<path d="M26.9 186h1v.3h-.6v.2h.6v.2h-.6v.2h.6v.3h-1z"/>
<path d="M27.8 182.1l.1-.1 .1 .4v.9z"/>
<path d="M28 187.5l.1 .3z"/>
<path d="M28 183.5l.2 .5z"/>
<path d="M28.2 187.5h.3l-.1 .3z"/>
<path d="M28.4 183.7l.1 1-.2-.7 .1 .2z"/>
<path d="M28.5 184.8v.1z"/>
<path d="M28.6 185.1v.1z"/>
<path d="M28.6 185.4v.1z"/>
<path d="M28.5 187.5h.3l-.1 .1h.1l-.1 .1 .1 .1h-.3z"/>
<path d="M27.6 182l-.2 .9 .2 .8h.2l-.1-.3 .2 .1v.1a2.08 2.08 0 0 1 .6 1.9l.4 .3h-.7l-.1-1.3-.2-.2-.2 .4-.4 .7-.2-.1 .2 .3a.41 .41 0 0 1-.4-.3l.3-.5h.4l.2-.2v-.4l-.2 .6h-.4l.3-.3-.1-1.3a.89 .89 0 0 1 .1-1.1z"/>
<path d="M29.2 181.3l-.1 .4z"/>
<path d="M28.9 187.5h.3l-.2 .1 .2 .1a.18 .18 0 0 1-.2 .1 .18 .18 0 0 1-.1-.3z"/>
<path d="M28.2 186h.3l.1 .5 .1-.1a.55 .55 0 0 1 .7-.4l-.1 .2a.32 .32 0 0 0-.3 .3 .32 .32 0 0 0 .2 .3l.3 .4h-.2a.47 .47 0 0 1-.5-.5l-.2 .2-.1 .3h-.3z"/>
<path d="M29.3 181.4v.1z"/>
<path d="M29.3 187.5l.2 .1 .1-.1v.3l-.1-.1-.2 .1z"/>
<path d="M29.2 181.8l-.1 .4a.29 .29 0 0 0 .2 .4v-.5l.2 .5a.53 .53 0 0 1-.1 .7l.1 .2h-.1v.7h.2l-.1 1.2v-1.1a.16 .16 0 0 0-.2 .1 .16 .16 0 0 0 .1 .2l-.1 .1v1l.6 .1h-.7l.1-2.6a.4 .4 0 0 0 .1-.6 .2 .2 0 0 1-.3 .1 .2 .2 0 0 1 0-.3z"/>
<path d="M29.5 182.1l.2 .1z"/>
<path d="M29.4 181.4l.5 .4-.1 .1-.3-.3 .1 .4-.1 .1 .1 .2 .2 .6 .2 .1h-.2v.5h-.2v-.1h.1v-.4l-.3-.8 .2-.2z"/>
<path d="M29.6 183.8v.1z"/>
<path d="M29.5 181.6l.1 .3z"/>
<path d="M29.7 182v.4l-.1-.1z"/>
<path d="M29.7 181.6l.1 .1z"/>
<path d="M29.9 187.5v.3z"/>
<path d="M29.8 182.1l.1 .7z"/>
<path d="M30.2 187.5v.3z"/>
<path d="M30.2 182.5l1-.5-.9 .5z"/>
<path d="M30.4 187.5h.3l-.3 .3v-.2h.1z"/>
<path d="M29.6 186.5l1-.4-.1 .3-.5 .2 .5 .2v.3l-.9-.4z"/>
<path d="M30.4 182.6l1.1-.7v.1l-.5 .3a.42 .42 0 0 0-.4 .4h.1l-.1 .1z"/>
<path d="M30.7 187.5h.3l-.2 .1 .2 .1-.3 .1 .2-.1z"/>
<path d="M31.2 187.5l.2 .3h-.3v-.2l.2 .1-.2-.1z"/>
<path d="M30.8 186.5l.9-.4a.3 .3 0 0 1-.1 .4 .3 .3 0 0 1-.3 .1h-.2l.6 .2v.3l-.9-.4z"/>
<path d="M31.6 187.7h.1z"/>
<path d="M222.5 100.9l.8-.3v2a1.02 1.02 0 0 1-1-.6 1.02 1.02 0 0 1 .2-1.1z"/>
<path d="M223.8 100.6a1.02 1.02 0 0 1 1 1 1.02 1.02 0 0 1-1 1z"/>
<circle cx="50.1" cy="182.8" r=".32"/>
<circle cx="52" cy="182.8" r=".31"/>
<circle cx="52.2" cy="184.3" r=".31"/>
<circle cx="53.3" cy="185.5" r=".32"/>
<circle cx="53.6" cy="183.2" r=".3"/>
<circle cx="54.7" cy="184.3" r=".31"/>
</g>
<path d="M171.4 116.8v1.3M175.3 116.8v1.3M179.1 116.8v1.3M219.7 101.6h2.5M222.5 100.9l.8-.3v2a1.02 1.02 0 0 1-1-.6 1.02 1.02 0 0 1 .2-1.1zM223.8 100.6a1.02 1.02 0 0 1 1 1 1.02 1.02 0 0 1-1 1zM224.8 101.6h2.5M171.4 127v1.3h1.3l-1.3 1.2-1.2-1.2h1.2M171.4 123.2v1.3M175.3 123.2v1.3M179.1 123.2v1.3" fill="none" stroke="#840000" stroke-width=".18"/>
<path d="M170.4 118.1h2.1v5.1h-2.1zM174.2 118.1h2.1v5.1h-2.1zM178.1 118.1h2v5.1h-2z" fill="none" stroke="#840000" stroke-width=".25"/>
<path d="M178.4 123.4v.8" fill="none" stroke="#006464" stroke-width=".18"/>
<path d="M55.9 123.2h2.5v7.6h-2.5z" fill="#ffffc2"/>
<path d="M55.9 123.2h2.5v7.6h-2.5z" fill="none" stroke="#840000" stroke-width=".25"/>
<path d="M52.1 124.5h3.8M52.1 127h3.8M52.1 129.5h3.8M55.9 124.3h1.2v.3h-1.2zM55.9 126.9h1.2v.2h-1.2zM55.9 129.4h1.2v.3h-1.2z" fill="none" stroke="#840000" stroke-width=".18"/>
<path d="M55.9 114.3h2.5v7.6h-2.5z" fill="#ffffc2"/>
<path d="M176.8 90.2h2v5.1h-2zM55.9 114.3h2.5v7.6h-2.5z" fill="none" stroke="#840000" stroke-width=".25"/>
<g fill="none" stroke="#840000" stroke-width=".18">
<path d="M168.9 33v1.3h1.3l-1.3 1.3-1.3-1.3h1.3M168.9 33h.1M177.8 63.5h.1M177.8 61v2.5M177.8 61l-.8 1.2M177.8 61l.8 1.2M254 69.9v1.2h1.3l-1.3 1.3-1.3-1.3h1.3M254 69.9h.1M254 62.2v2.8M254 67.1v2.8M177.8 88.9v1.3M177.8 95.3v1.2"/>
<path d="M254 82.6h.1M254 90.2v1.2h1.3l-1.3 1.3-1.3-1.3h1.3M254 90.2h.1M254 80l-.8 1.3M254 80l.8 1.3M254 80v5.3M254 87.4v2.8M52.1 115.6h3.8M52.1 118.1h3.8M55.9 115.4h1.2v.3h-1.2zM55.9 118h1.2v.2h-1.2zM219.7 104.1h2.5"/>
<path d="M222.5 103.4l.8-.3v2.1a1.02 1.02 0 0 1-1-.7 1.02 1.02 0 0 1 .2-1.1zM223.8 103.1a1.02 1.02 0 0 1 1 1 1.02 1.02 0 0 1-1 1.1zM224.8 104.1h2.5M52.1 120.7h3.8M55.9 120.5h1.2v.3h-1.2zM25.4 158.8v1.2h1.3l-1.3 1.3-1.3-1.3h1.3M25.4 158.8h.1M25.4 156.2v2.6M33 156.2v2.6M40.6 156.2v2.6M49.5 156.2v2.6"/>
</g>
<g fill="#840000" stroke="#840000" stroke-width=".18">
<path d="M222.5 103.4l.8-.3v2.1a1.02 1.02 0 0 1-1-.7 1.02 1.02 0 0 1 .2-1.1z"/>
<path d="M223.8 103.1a1.02 1.02 0 0 1 1 1 1.02 1.02 0 0 1-1 1.1z"/>
</g>
<path d="M180.5 57.7l-.4 1.3M249.3 66.6h.6M255.7 76.8h.4l.3 .2-.1 .4h-.6M249.3 86.9h.6" fill="none" stroke="#006464" stroke-width=".18"/>
<g fill="none" stroke="#840000" stroke-width="1.3">
<circle cx="25.4" cy="154.9" r="1.27"/>
<circle cx="33" cy="154.9" r="1.27"/>
<circle cx="40.6" cy="154.9" r="1.27"/>
<circle cx="49.5" cy="154.9" r="1.27"/>
</g>
<path d="M252 65.3h4M252 66.8h4M252 85.6h4M252 87.1h4" fill="none" stroke="#840000" stroke-width=".51"/>
<path d="M111.8 77.5h15.2v43.2h-15.2z" fill="#ffffc2"/>
<path d="M111.8 77.5h15.2v43.2h-15.2zM101.9 86.4h2v5h-2zM99.3 114.3h2v5.1h-2zM103.1 114.3h2.1v5.1h-2.1z" fill="none" stroke="#840000" stroke-width=".25"/>
<g fill="none" stroke="#840000" stroke-width=".18">
<path d="M102.9 69.9h.1M102.9 67.3l-.8 1.3M102.9 67.3l.7 1.3M102.9 67.3v2.6M106.7 69.9v2.7M106.7 74.7v2.8M119.4 74.9v2.6M102.9 85.1v1.3M102.9 91.4v1.3M109.2 80h2.6M109.2 82.6h2.6M109.2 92.7h2.6"/>
<path d="M127 80h2.5M127 82.6h2.5M127 92.7h2.5M127 85.1h2.5M127 87.6h2.5M127 90.2h2.5M127 95.3h2.5M127 97.8h2.5M100.3 113v1.3M100.3 119.4v1.3M104.1 113v1.3M104.1 119.4v1.3"/>
<path d="M109.2 105.4h2.6M109.2 108h2.6M109.2 110.5h2.6M127 105.4h2.5M127 108h2.5M127 110.5h2.5M127 100.3h2.5M127 102.9h2.5M127 113h2.5M127 115.6h2.5M127 118.1h2.5M151.1 109.2h.1"/>
<path d="M151.1 106.7l-.7 1.3M151.1 106.7l.8 1.3M151.1 106.7v2.5M119.4 120.7v2.5M254 123.2h.1M254 120.7l-.8 1.2M254 120.7l.8 1.2M254 120.7v2.5"/>
</g>
<path d="M105.6 64.1l-.4 1.2M115.7 74.8h.4M115.7 74.2h.6M112.5 91.7h5.5M153.9 103.4l-.5 1.3M255.7 117.4h.4l.3 .3-.1 .3-.6 .1" fill="none" stroke="#006464" stroke-width=".18"/>
<path d="M128.5 94.8h.7M110.7 105h.8" fill="none" stroke="#a90000" stroke-width=".18"/>
<path d="M104.6 72.9h4.1M104.6 74.4h4.1" fill="none" stroke="#840000" stroke-width=".51"/>
<path d="M82.5 102.9h7.7v10.1h-7.7z" fill="#ffffc2"/>
<g fill="none" stroke="#840000" stroke-width=".18">
<path d="M78.7 105.4h5.1M78.7 108h5.1M78.7 110.5h5.1M88.7 104.2l-3.9 1.1M88.7 106.8l-3.9 1M88.7 109.3l-3.9 1.1M88.9 105.4h5.1M88.9 108h5.1M88.9 110.5h5.1"/>
<circle cx="84.3" cy="105.4" r=".51"/>
<circle cx="84.3" cy="110.5" r=".51"/>
<circle cx="84.3" cy="108" r=".51"/>
<circle cx="88.4" cy="108" r=".51"/>
<circle cx="88.4" cy="110.5" r=".51"/>
<circle cx="88.4" cy="105.4" r=".51"/>
</g>
<path d="M82.5 102.9h7.7v10.1h-7.7z" fill="none" stroke="#840000" stroke-width=".25"/>
<path d="M157.5 106.7h7.6v10.1h-7.6z" fill="#ffffc2"/>
<g fill="none" stroke="#840000" stroke-width=".18">
<path d="M76.2 105.4h.1M76.2 102.9l-.8 1.2M76.2 102.9l.8 1.2M76.2 102.9v2.5M96.5 113v1.3M96.5 119.4v1.3M153.7 109.2h5M153.7 111.8h5M153.7 114.3h5M163.7 108.1l-3.9 1M163.7 110.6l-3.9 1M163.7 113.1l-3.9 1.1"/>
<path d="M163.8 109.2h5.1M163.8 111.8h5.1M163.8 114.3h5.1"/>
<circle cx="159.3" cy="114.3" r=".51"/>
<circle cx="159.3" cy="109.2" r=".51"/>
<circle cx="159.3" cy="111.8" r=".51"/>
<circle cx="163.3" cy="114.3" r=".51"/>
<circle cx="163.3" cy="109.2" r=".51"/>
<circle cx="163.3" cy="111.8" r=".51"/>
</g>
<path d="M95.5 114.3h2v5.1h-2zM157.5 106.7h7.6v10.1h-7.6z" fill="none" stroke="#840000" stroke-width=".25"/>
<path d="M78.9 99.6l-.4 1.3" fill="none" stroke="#006464" stroke-width=".18"/>
<path d="M55.9 105.4h2.5v7.6h-2.5z" fill="#ffffc2"/>
<path d="M55.9 105.4h2.5v7.6h-2.5z" fill="none" stroke="#840000" stroke-width=".25"/>
<path d="M237.5 33v1.3h1.3l-1.3 1.3-1.3-1.3h1.3M237.5 33h.1M52.1 106.7h3.8M52.1 109.2h3.8M52.1 111.8h3.8M55.9 106.6h1.2v.2h-1.2zM55.9 109.1h1.2v.2h-1.2zM55.9 111.6h1.2v.3h-1.2z" fill="none" stroke="#840000" stroke-width=".18"/>
<path d="M24.1 96.5h2.6v7.6h-2.6z" fill="#ffffc2"/>
<path d="M24.1 96.5h2.6v7.6h-2.6z" fill="none" stroke="#840000" stroke-width=".25"/>
<path d="M25.4 97.7h1.3v.2h-1.3zM26.7 97.8h3.8M35.6 96.5h.1M35.6 94l-.8 1.3M35.6 94l.7 1.3M35.6 94v2.5M25.4 100.2h1.3v.3h-1.3zM25.4 102.7h1.3v.3h-1.3zM26.7 100.3h3.8M26.7 102.9h3.8" fill="none" stroke="#840000" stroke-width=".18"/>
<path d="M37.2 90.7h.5l.2 .3-.1 .4h-.6" fill="none" stroke="#006464" stroke-width=".18"/>
<path d="M55.9 96.5h2.5v7.6h-2.5z" fill="#ffffc2"/>
<path d="M55.9 96.5h2.5v7.6h-2.5z" fill="none" stroke="#840000" stroke-width=".25"/>
<path d="M33 95.3l1-.7-1-.6-1 .6 1 .7v1.2M33 96.5h.1M52.1 97.8h3.8M55.9 97.7h1.2v.2h-1.2zM35.6 102.9v1.2h1.2l-1.2 1.3-1.3-1.3h1.3M35.6 102.9h.1M52.1 100.3h3.8M52.1 102.9h3.8M55.9 100.2h1.2v.3h-1.2zM55.9 102.7h1.2v.3h-1.2z" fill="none" stroke="#840000" stroke-width=".18"/>
<path d="M260.3 24.1h5.1v7.7h-5.1z" fill="#ffffc2"/>
<path d="M121.9 26.7h2.6l-1.3 2.5zM121.9 29.2h2.6M260.3 24.1h5.1v7.7h-5.1z" fill="none" stroke="#840000" stroke-width=".25"/>
<g fill="none" stroke="#840000" stroke-width=".18">
<path d="M86.4 24.1h.1M86.4 34.3v1.3h1.2l-1.2 1.2-1.3-1.2h1.3M86.4 34.3h.1M86.4 21.6v5.3M86.4 29v2.8M86.4 21.6l-.8 1.3M86.4 21.6l.7 1.3M123.2 24.1v7.7M124 31l1.5 1.5v-.7v.7h-.8M124 29.7l1.5 1.5v-.7v.7h-.8M256.5 25.4h3.8M256.5 27.9h3.8"/>
<path d="M256.5 30.5h3.8M260.3 25.3h1.3v.2h-1.3zM260.3 27.8h1.3v.3h-1.3zM260.3 30.4h1.3v.2h-1.3zM264.2 25.3h1.2v.2h-1.2zM264.2 27.8h1.2v.3h-1.2zM264.2 30.4h1.2v.2h-1.2zM265.4 25.4h3.8M265.4 27.9h3.8M265.4 30.5h3.8M271.8 33v1.3h1.2l-1.2 1.3-1.3-1.3h1.3M271.8 33h.1"/>
<path d="M96.5 123.2v1.3h1.3l-1.3 1.2-1.3-1.2h1.3"/>
</g>
<path d="M88.1 19.6h.6M263.6 19.6h.7M261.6 21.3l-.3 .1" fill="none" stroke="#006464" stroke-width=".18"/>
<path d="M84.3 27.2h4.1M84.3 28.7h4.1" fill="none" stroke="#840000" stroke-width=".51"/>
<path d="M95.2 21.6h10.2v10.2h-10.2z" fill="#ffffc2"/>
<path d="M95.2 21.6h10.2v10.2h-10.2zM114.3 33.3h5.1v2h-5.1z" fill="none" stroke="#840000" stroke-width=".25"/>
<g fill="none" stroke="#840000" stroke-width=".18">
<path d="M92.7 24.1h2.5M92.7 26.7h2.5M100.3 31.8v2.5M105.4 24.1h2.5M110.5 24.1v2.8M110.5 29v2.8M113 34.3h1.3M119.4 34.3h1.2M123.2 24.1h.1M123.2 21.6l-.8 1.3M123.2 21.6l.8 1.3M123.2 21.6v2.5"/>
<path d="M254 25.4h.1M254 22.9l-.8 1.2M254 22.9l.8 1.2M254 22.9v2.5"/>
</g>
<path d="M106.8 18.5l.2-.1a.68 .68 0 0 1 .5 .6 .68 .68 0 0 1-.5 .6l-.2-.1-.1-.4zM125.9 18.4l-.4 1.2M256.7 19.6l-.4 1.3" fill="none" stroke="#006464" stroke-width=".18"/>
<path d="M108.5 27.2h4M108.5 28.7h4" fill="none" stroke="#840000" stroke-width=".51"/>
<path d="M226.1 24.1h5v7.7h-5z" fill="#ffffc2"/>
<path d="M226.1 24.1h5v7.7h-5z" fill="none" stroke="#840000" stroke-width=".25"/>
<g fill="none" stroke="#840000" stroke-width=".18">
<path d="M25.4 33h.1M25.4 25.4h.1M27.9 33h.1M27.9 25.4h.1M27.9 25.4h3.8M27.9 27.9h3.8M27.9 30.5h3.8M36.8 25.4h3.8M36.8 27.9h3.8M36.8 30.5h3.8M55.9 22.9v1.2M55.9 29.2v1.3"/>
<path d="M58.4 22.9h.1M58.4 22.9v1.2M58.4 29.2v1.3M86.4 24.1h.1M86.4 24.1v2.8M86.4 29v2.8M92.7 24.1h2.5M92.7 26.7h2.5M100.3 31.8v2.5M105.4 24.1h2.5M110.5 24.1v2.8M110.5 29v2.8"/>
<path d="M113 34.3h1.3M119.4 34.3h1.2M120.6 24.1h.1M123.2 24.1h.1M123.2 24.1v2.6M123.2 29.2v2.6M151.1 25.4h.1M153.7 25.4h3.8M153.7 27.9h3.8M153.7 30.5h3.8M162.6 25.4h3.8M162.6 27.9h3.8"/>
<path d="M162.6 30.5h3.8M185.4 25.4h.1M188 25.4h3.8M188 27.9h3.8M188 30.5h3.8M196.8 25.4h3.9M196.8 27.9h3.9M196.8 30.5h3.9M219.7 25.4h.1M222.2 25.4h3.9M222.2 27.9h3.9M222.2 30.5h3.9"/>
<path d="M226.1 25.3h1.2v.2h-1.2zM226.1 27.8h1.2v.3h-1.2zM226.1 30.4h1.2v.2h-1.2zM229.9 25.3h1.2v.2h-1.2zM229.9 27.8h1.2v.3h-1.2zM229.9 30.4h1.2v.2h-1.2zM231.1 25.4h3.8M231.1 27.9h3.8M231.1 30.5h3.8M254 25.4h.1M256.5 25.4h3.8M256.5 27.9h3.8"/>
<path d="M256.5 30.5h3.8M265.4 25.4h3.8M265.4 27.9h3.8M265.4 30.5h3.8M33 61h.1M102.9 69.9h.1M106.7 69.9v2.7M106.7 74.7v2.8M119.4 74.9v2.6M177.8 63.5h.1M181.6 63.5v2.8M181.6 68.3v2.8"/>
<path d="M184.1 73.7h5.1M184.1 76.2h5.1M201.9 66v5.1M214.6 73.7h5.1M214.6 76.2h5.1M214.6 78.7h5.1M254 69.9h.1M254 62.2h.1M254 62.2v2.8M254 67.1v2.8M33 96.5h.1M35.6 96.5h.1"/>
<path d="M109.2 80h2.6M109.2 82.6h2.6M109.2 92.7h2.6M127 80h2.5M127 82.6h2.5M127 92.7h2.5M127 85.1h2.5M127 87.6h2.5M127 90.2h2.5M127 95.3h2.5M127 97.8h2.5M184.1 96.5h5.1"/>
<path d="M184.1 88.9h5.1M184.1 91.4h5.1M214.6 96.5h7.6M214.6 88.9h5.1M214.6 91.4h5.1M214.6 81.3h5.1M214.6 83.8h5.1M214.6 86.4h5.1M214.6 99.1h7.6M224.8 96.5h2.5M224.8 99.1h2.5M254 82.6h.1"/>
<path d="M254 90.2h.1M254 82.6v2.7M254 87.4v2.8M76.2 105.4h.1M78.7 105.4h5.1M78.7 108h5.1M78.7 110.5h5.1M88.9 105.4h5.1M88.9 108h5.1M88.9 110.5h5.1M96.5 113v1.3M96.5 119.4v1.3"/>
<path d="M100.3 113v1.3M100.3 119.4v1.3M109.2 105.4h2.6M109.2 108h2.6M109.2 110.5h2.6M127 105.4h2.5M127 108h2.5M127 110.5h2.5M127 100.3h2.5M127 102.9h2.5M127 113h2.5M127 115.6h2.5"/>
<path d="M127 118.1h2.5M151.1 109.2h.1M153.7 109.2h5M153.7 111.8h5M153.7 114.3h5M163.8 109.2h5.1M163.8 111.8h5.1M163.8 114.3h5.1M171.4 116.8v1.3M175.3 116.8v1.3M184.1 109.2h5.1M184.1 111.8h5.1"/>
<path d="M184.1 114.3h5.1M201.9 116.8v5.1M214.6 109.2h5.1M214.6 111.8h5.1M214.6 114.3h5.1M214.6 101.6h7.6M214.6 104.1h7.6M214.6 106.7h5.1M224.8 101.6h2.5M224.8 104.1h2.5M254 110.5h.1M254 102.9h.1"/>
<path d="M254 102.9v2.8M254 107.7v2.8M119.4 120.7v2.5M171.4 123.2v1.3M175.3 123.2v1.3M254 123.2h.1M254 130.8h.1M254 123.2v2.8M254 128v2.8M25.4 158.8h.1M25.4 156.2v2.6"/>
</g>
<g fill="none" stroke="#006464" stroke-width=".18">
<path d="M61.1 17.1l-.4 1.3M88.1 19.6h.6M106.8 18.5l.2-.1a.68 .68 0 0 1 .5 .6 .68 .68 0 0 1-.5 .6l-.2-.1-.1-.4zM125.9 18.4l-.4 1.2M153.9 19.6l-.5 1.3M188.1 19.6l-.4 1.3M222.4 19.6l-.4 1.3M256.7 19.6l-.4 1.3M263.6 19.6h.7M27.1 20.9h.6M158.7 21.3l-.2 .1M193 21.3l-.2 .1"/>
<path d="M227.3 21.3l-.2 .1M261.6 21.3l-.3 .1M34.7 55.2h.5l.2 .2-.1 .4-.6 .1M180.5 57.7l-.4 1.3M255.7 56.5h.4l.3 .2-.1 .4h-.6M105.6 64.1l-.4 1.2M115.7 74.8h.4M115.7 74.2h.6M190.6 68.5h.4M190.6 67.9h.6M216.8 68h.6M216.8 68.4l.4 .2 .2 .3-.3 .3-.5-.1"/>
<path d="M249.3 66.6h.6M255.7 76.8h.4l.3 .2-.1 .4h-.6M37.2 90.7h.5l.2 .3-.1 .4h-.6M78.9 99.6l-.4 1.3M112.5 91.7h5.5M190.5 95.5h5.5M249.3 86.9h.6M255.7 97.1h.4l.3 .2-.1 .4-.6 .1M153.9 103.4l-.5 1.3M249.3 107.3h.6M255.7 117.4h.4l.3 .3-.1 .3-.6 .1M249.3 127.6h.6"/>
</g>
<path d="M226.3 73.1h.7M263.5 64.3h.7" fill="none" stroke="#0f0f0f" stroke-width=".18"/>
<g fill="none" stroke="#009600" stroke-width=".18">
<path d="M19 30.5h8.9M25.4 25.4h2.5M27.9 27.9h-2.5v5.1h2.5M40.6 30.5h5.1M55.9 22.9h2.5M55.9 30.5v7.6M58.4 30.5v7.6M86.4 31.8v2.5h26.6M86.4 24.1h6.3M90.2 24.1v2.6h2.5M107.9 24.1h15.3M110.5 31.8v2.5"/>
<path d="M123.2 31.8v2.5h-2.6M144.8 27.9h8.9M144.8 30.5h8.9M151.1 25.4h2.6M166.4 27.9h8.9M166.4 30.5h8.9M166.4 25.4h2.5v7.6M179.1 27.9h8.9M179.1 30.5h8.9M185.4 25.4h2.6M200.7 27.9h8.8M200.7 30.5h8.8"/>
<path d="M200.7 25.4h2.5v7.6M213.4 27.9h8.8M213.4 30.5h8.8M219.7 25.4h2.5M234.9 27.9h8.9M234.9 30.5h8.9M234.9 25.4h2.6v7.6M247.6 27.9h8.9M247.6 30.5h8.9M254 25.4h2.5M269.2 27.9h8.9M269.2 30.5h8.9"/>
<path d="M269.2 25.4h2.6v7.6M33 63.5h2.6M33 61h2.6M106.7 77.5v45.7M119.4 74.9v-5h-16.5v15.2M171.4 73.7h12.7M171.4 76.2h12.7M181.6 71.1v55.9M201.9 66v-2.5h-24.1v25.4M219.7 73.7h7.6M219.7 76.2h7.6M219.7 78.7h7.6"/>
<path d="M254 62.2h10.2M254 69.9h10.2M257.8 67.3h6.4M257.8 64.8h6.4M30.5 97.8h21.6M33 96.5h2.6v3.8M50.8 97.8v26.7h1.3M96.5 82.6h12.7M96.5 80h12.7M102.9 92.7h6.3M129.5 90.2h6.4M129.5 82.6h6.4"/>
<path d="M129.5 85.1h6.4M129.5 97.8h6.4M129.5 92.7h6.4M129.5 80h6.4M129.5 87.6h6.4M129.5 95.3h6.4M177.8 96.5h6.3M219.7 83.8h7.6M219.7 88.9h7.6M219.7 86.4h7.6M219.7 81.3h7.6M219.7 91.4h7.6"/>
<path d="M227.3 96.5h7.6M227.3 99.1h7.6M254 90.2h10.2M254 82.6h10.2M257.8 85.1h6.4M257.8 87.6h6.4M30.5 102.9h21.6M30.5 100.3h21.6M48.3 111.8h3.8M48.3 102.9v26.6h3.8M49.5 100.3v26.7h2.6M49.5 109.2h2.6"/>
<path d="M49.5 118.1h2.6M50.8 106.7h1.3M50.8 115.6h1.3M76.2 108h2.5M78.7 105.4h-2.5v5.1h2.5M94 105.4h15.2M94 108h15.2M94 110.5h15.2M96.5 110.5v2.5M100.3 108v5M104.1 105.4v7.6M151.1 111.8h2.6"/>
<path d="M153.7 109.2h-2.6v5.1h2.6M168.9 109.2h15.2M168.9 111.8h15.2M168.9 114.3h15.2M171.4 114.3v2.5M175.3 111.8v5M179.1 109.2v7.6M227.3 104.1h7.6M227.3 101.6h7.6M254 102.9h10.2M254 110.5h10.2M257.8 105.4h6.4"/>
<path d="M257.8 108h6.4M48.3 120.7h3.8M96.5 123.2h22.9M201.9 121.9v5.1h-30.5M254 123.2h10.2M254 130.8h10.2M257.8 128.3h6.4M257.8 125.7h6.4M25.4 158.8h24.1"/>
</g>
<g fill="none" stroke="#000084" stroke-width=".18">
<path d="M40 24.8l1.2 1.2M40 27.3l1.2 1.2M41.2 24.8l-1.2 1.2M41.2 27.3l-1.2 1.2M144.2 29.9l1.2 1.2M145.4 29.9l-1.2 1.2M178.5 29.9l1.2 1.2M179.7 29.9l-1.2 1.2M212.8 29.9l1.2 1.2M214 29.9l-1.2 1.2M247 29.9l1.3 1.2M248.3 29.9l-1.3 1.2"/>
<path d="M128.9 99.7l1.2 1.2M130.1 99.7l-1.2 1.2M183.5 88.3l1.3 1.2M183.5 90.8l1.3 1.2M184.8 88.3l-1.3 1.2M184.8 90.8l-1.3 1.2M128.9 117.5l1.2 1.2M128.9 107.3l1.2 1.3M128.9 104.8l1.2 1.2M128.9 102.3l1.2 1.2M128.9 115l1.2 1.2M128.9 112.4l1.2 1.2"/>
<path d="M128.9 109.9l1.2 1.2M130.1 117.5l-1.2 1.2M130.1 107.3l-1.2 1.3M130.1 104.8l-1.2 1.2M130.1 102.3l-1.2 1.2M130.1 115l-1.2 1.2M130.1 112.4l-1.2 1.2M130.1 109.9l-1.2 1.2M219.1 111.2l1.2 1.2M219.1 106.1l1.2 1.2M219.1 113.7l1.2 1.2M219.1 108.6l1.2 1.2"/>
<path d="M220.3 111.2l-1.2 1.2M220.3 106.1l-1.2 1.2M220.3 113.7l-1.2 1.2M220.3 108.6l-1.2 1.2"/>
</g>
<g fill="none" stroke="#0000c2" stroke-width=".18">
<path d="M12.7 12.7h55.9v31.8h-55.9zM69.8 12.7h71.2v31.8h-71.2zM142.2 12.7h141v31.8h-141zM148.2 14.1l-.3 .1M156.4 14.6v.3M12.7 45.7h55.9v31.8h-55.9zM69.8 45.7h71.2v97.8h-71.2zM84.1 47.1l.2 .4-.6 .1M84.3 47.9l-.2 .1M84.9 47.1v.9M85.2 47.1l-.3 .3M142.2 45.7h96.6v97.8h-96.6z"/>
<path d="M157.3 47.1l-.3 .1M240 45.7h43.2v97.8h-43.2zM255.1 47.1l-.3 .1M12.7 78.7h55.9v64.8h-55.9zM77.3 94.2l.1 .6-.2 .5M150.9 96.7l.2 .7-.2 .4M12.7 144.8h55.9v25.4h-55.9zM21.4 146.9l.2 .2 .4-.1M22 146.2v1l-.3 .3-.3-.1M22 146.3l-.4-.1-.2 .1M12.7 171.5h55.9v25.4h-55.9zM20.4 172.9h.4"/>
<path d="M20.8 172.9v1l-.2 .2h-.3M20.8 173.7h-.4"/>
</g>
<path d="M128.5 94.8h.7M217.4 96.1h.7M110.7 105h.8" fill="none" stroke="#a90000" stroke-width=".18"/>
<path d="M35.6 61h3.8M35.6 63.5h3.8" fill="none" stroke="#9c9b98" stroke-width=".18"/>
<path d="M36.8 58.8l7.7 6.8M44.5 58.8l-7.7 6.8" fill="none" stroke="#e12e31" stroke-width=".46"/>
<g fill="#009600" stroke="#009600" stroke-width=".18">
<circle cx="177.8" cy="63.5" r=".46"/>
<circle cx="179.1" cy="127" r=".46"/>
<circle cx="171.4" cy="127" r=".46"/>
<circle cx="181.6" cy="127" r=".46"/>
<circle cx="175.3" cy="127" r=".46"/>
<circle cx="179.1" cy="109.2" r=".46"/>
<circle cx="171.4" cy="114.3" r=".46"/>
<circle cx="175.3" cy="111.8" r=".46"/>
<circle cx="151.1" cy="111.8" r=".46"/>
<circle cx="151.1" cy="109.2" r=".46"/>
<circle cx="254" cy="90.2" r=".46"/>
<circle cx="181.6" cy="63.5" r=".46"/>
<circle cx="254" cy="62.2" r=".46"/>
<circle cx="254" cy="69.9" r=".46"/>
<circle cx="254" cy="82.6" r=".46"/>
<circle cx="254" cy="130.8" r=".46"/>
<circle cx="254" cy="123.2" r=".46"/>
<circle cx="254" cy="110.5" r=".46"/>
<circle cx="254" cy="102.9" r=".46"/>
<circle cx="86.4" cy="34.3" r=".46"/>
<circle cx="58.4" cy="22.9" r=".46"/>
<circle cx="86.4" cy="24.1" r=".46"/>
<circle cx="25.4" cy="33" r=".46"/>
<circle cx="49.5" cy="118.1" r=".46"/>
<circle cx="48.3" cy="120.7" r=".46"/>
<circle cx="40.6" cy="158.8" r=".46"/>
<circle cx="48.3" cy="111.8" r=".46"/>
<circle cx="50.8" cy="115.6" r=".46"/>
<circle cx="25.4" cy="158.8" r=".46"/>
<circle cx="33" cy="158.8" r=".46"/>
<circle cx="96.5" cy="123.2" r=".46"/>
<circle cx="106.7" cy="123.2" r=".46"/>
<circle cx="104.1" cy="123.2" r=".46"/>
<circle cx="106.7" cy="69.9" r=".46"/>
<circle cx="104.1" cy="105.4" r=".46"/>
<circle cx="102.9" cy="69.9" r=".46"/>
<circle cx="49.5" cy="100.3" r=".46"/>
<circle cx="50.8" cy="97.8" r=".46"/>
<circle cx="76.2" cy="105.4" r=".46"/>
<circle cx="50.8" cy="106.7" r=".46"/>
<circle cx="49.5" cy="109.2" r=".46"/>
<circle cx="48.3" cy="102.9" r=".46"/>
<circle cx="35.6" cy="96.5" r=".46"/>
<circle cx="35.6" cy="100.3" r=".46"/>
<circle cx="35.6" cy="102.9" r=".46"/>
<circle cx="76.2" cy="108" r=".46"/>
<circle cx="96.5" cy="110.5" r=".46"/>
<circle cx="100.3" cy="108" r=".46"/>
<circle cx="100.3" cy="123.2" r=".46"/>
<circle cx="123.2" cy="24.1" r=".46"/>
<circle cx="120.6" cy="24.1" r=".46"/>
<circle cx="100.3" cy="34.3" r=".46"/>
<circle cx="110.5" cy="34.3" r=".46"/>
<circle cx="110.5" cy="24.1" r=".46"/>
<circle cx="90.2" cy="24.1" r=".46"/>
<circle cx="27.9" cy="25.4" r=".46"/>
</g>
<use href="#words"/>
</svg>
